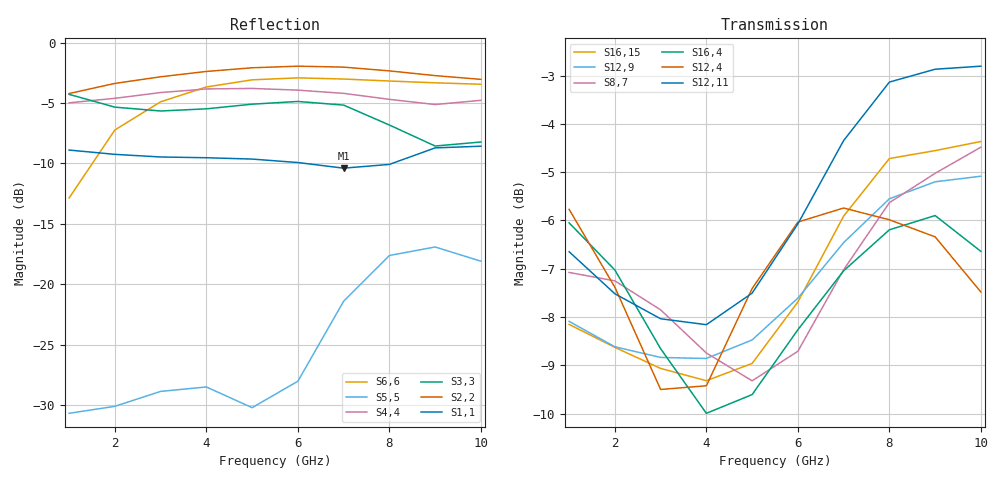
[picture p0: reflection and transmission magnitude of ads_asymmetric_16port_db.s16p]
! Created Fri Aug 21 14:56:00 2026
! 16 Port Network Data from SP1.SP block
! freq  dbS1_1  angS1_1  dbS1_2  angS1_2  dbS1_3  angS1_3  dbS1_4  angS1_4
!  dbS1_5  angS1_5  dbS1_6  angS1_6  dbS1_7  angS1_7  dbS1_8  angS1_8
!  dbS1_9  angS1_9  dbS1_10  angS1_10  dbS1_11  angS1_11  dbS1_12  angS1_12
!  dbS1_13  angS1_13  dbS1_14  angS1_14  dbS1_15  angS1_15  dbS1_16  angS1_16
!  dbS2_1  angS2_1  dbS2_2  angS2_2  dbS2_3  angS2_3  dbS2_4  angS2_4
!  dbS2_5  angS2_5  dbS2_6  angS2_6  dbS2_7  angS2_7  dbS2_8  angS2_8
!  dbS2_9  angS2_9  dbS2_10  angS2_10  dbS2_11  angS2_11  dbS2_12  angS2_12
!  dbS2_13  angS2_13  dbS2_14  angS2_14  dbS2_15  angS2_15  dbS2_16  angS2_16
!  dbS3_1  angS3_1  dbS3_2  angS3_2  dbS3_3  angS3_3  dbS3_4  angS3_4
!  dbS3_5  angS3_5  dbS3_6  angS3_6  dbS3_7  angS3_7  dbS3_8  angS3_8
!  dbS3_9  angS3_9  dbS3_10  angS3_10  dbS3_11  angS3_11  dbS3_12  angS3_12
!  dbS3_13  angS3_13  dbS3_14  angS3_14  dbS3_15  angS3_15  dbS3_16  angS3_16
!  dbS4_1  angS4_1  dbS4_2  angS4_2  dbS4_3  angS4_3  dbS4_4  angS4_4
!  dbS4_5  angS4_5  dbS4_6  angS4_6  dbS4_7  angS4_7  dbS4_8  angS4_8
!  dbS4_9  angS4_9  dbS4_10  angS4_10  dbS4_11  angS4_11  dbS4_12  angS4_12
!  dbS4_13  angS4_13  dbS4_14  angS4_14  dbS4_15  angS4_15  dbS4_16  angS4_16
!  dbS5_1  angS5_1  dbS5_2  angS5_2  dbS5_3  angS5_3  dbS5_4  angS5_4
!  dbS5_5  angS5_5  dbS5_6  angS5_6  dbS5_7  angS5_7  dbS5_8  angS5_8
!  dbS5_9  angS5_9  dbS5_10  angS5_10  dbS5_11  angS5_11  dbS5_12  angS5_12
!  dbS5_13  angS5_13  dbS5_14  angS5_14  dbS5_15  angS5_15  dbS5_16  angS5_16
!  dbS6_1  angS6_1  dbS6_2  angS6_2  dbS6_3  angS6_3  dbS6_4  angS6_4
!  dbS6_5  angS6_5  dbS6_6  angS6_6  dbS6_7  angS6_7  dbS6_8  angS6_8
!  dbS6_9  angS6_9  dbS6_10  angS6_10  dbS6_11  angS6_11  dbS6_12  angS6_12
!  dbS6_13  angS6_13  dbS6_14  angS6_14  dbS6_15  angS6_15  dbS6_16  angS6_16
!  dbS7_1  angS7_1  dbS7_2  angS7_2  dbS7_3  angS7_3  dbS7_4  angS7_4
!  dbS7_5  angS7_5  dbS7_6  angS7_6  dbS7_7  angS7_7  dbS7_8  angS7_8
!  dbS7_9  angS7_9  dbS7_10  angS7_10  dbS7_11  angS7_11  dbS7_12  angS7_12
!  dbS7_13  angS7_13  dbS7_14  angS7_14  dbS7_15  angS7_15  dbS7_16  angS7_16
!  dbS8_1  angS8_1  dbS8_2  angS8_2  dbS8_3  angS8_3  dbS8_4  angS8_4
!  dbS8_5  angS8_5  dbS8_6  angS8_6  dbS8_7  angS8_7  dbS8_8  angS8_8
!  dbS8_9  angS8_9  dbS8_10  angS8_10  dbS8_11  angS8_11  dbS8_12  angS8_12
!  dbS8_13  angS8_13  dbS8_14  angS8_14  dbS8_15  angS8_15  dbS8_16  angS8_16
!  dbS9_1  angS9_1  dbS9_2  angS9_2  dbS9_3  angS9_3  dbS9_4  angS9_4
!  dbS9_5  angS9_5  dbS9_6  angS9_6  dbS9_7  angS9_7  dbS9_8  angS9_8
!  dbS9_9  angS9_9  dbS9_10  angS9_10  dbS9_11  angS9_11  dbS9_12  angS9_12
!  dbS9_13  angS9_13  dbS9_14  angS9_14  dbS9_15  angS9_15  dbS9_16  angS9_16
!  dbS10_1  angS10_1  dbS10_2  angS10_2  dbS10_3  angS10_3  dbS10_4  angS10_4
!  dbS10_5  angS10_5  dbS10_6  angS10_6  dbS10_7  angS10_7  dbS10_8  angS10_8
!  dbS10_9  angS10_9  dbS10_10  angS10_10  dbS10_11  angS10_11  dbS10_12  angS10_12
!  dbS10_13  angS10_13  dbS10_14  angS10_14  dbS10_15  angS10_15  dbS10_16  angS10_16
!  dbS11_1  angS11_1  dbS11_2  angS11_2  dbS11_3  angS11_3  dbS11_4  angS11_4
!  dbS11_5  angS11_5  dbS11_6  angS11_6  dbS11_7  angS11_7  dbS11_8  angS11_8
!  dbS11_9  angS11_9  dbS11_10  angS11_10  dbS11_11  angS11_11  dbS11_12  angS11_12
!  dbS11_13  angS11_13  dbS11_14  angS11_14  dbS11_15  angS11_15  dbS11_16  angS11_16
!  dbS12_1  angS12_1  dbS12_2  angS12_2  dbS12_3  angS12_3  dbS12_4  angS12_4
!  dbS12_5  angS12_5  dbS12_6  angS12_6  dbS12_7  angS12_7  dbS12_8  angS12_8
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# ghz S db R 50
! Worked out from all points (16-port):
!   10 points, 1 GHz to 10 GHz, reference 50 ohm
!   strongest paths, dB at 1 GHz, 3 GHz, 6 GHz, 8 GHz, 10 GHz:
!     S12,11: -6.6, -8.0, -6.1, -3.1, -2.8
!     S12,4: -5.8, -9.5, -6.0, -6.0, -7.5
!     S16,4: -6.0, -8.7, -8.3, -6.2, -6.6
!     S8,7: -7.1, -7.9, -8.7, -5.6, -4.5
!     S12,9: -8.1, -8.8, -7.6, -5.6, -5.1
!     S16,15: -8.2, -9.1, -7.7, -4.7, -4.4
!   lowest |S11| = -10.4 dB at 7 GHz (marker M1), VSWR 1.87, Z = 26.8 - j1.48 ohm
!   |S11| at or under -10 dB: 6.146 GHz to 8.064 GHz (1.918 GHz wide, 27 % of centre)
